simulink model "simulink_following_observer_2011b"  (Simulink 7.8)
settings: Solver=ode3  StartTime=0.0  StopTime=15  FixedStep=1e-2  RelTol=1e-3
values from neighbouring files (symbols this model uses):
  A = [0 1 0 0    [following_observer.m]
  Av = [0 1 0 0    [parameter_variation.m]
  B = [0; 1/M1; 0; 0]    [following_observer.m]
  Bv = [0; 1/M1v; 0; 0]    [parameter_variation.m]
  C = [0 0 1 0]    [following_observer.m]
  H = [-K 1]*inv(M0)*[zeros(4,1); 1]    [following_observer.m]
  K = -acker(A,B,p)    [following_observer.m]
  L = -acker(A',C',q)'    [following_observer.m]
  x0 = [-0.5 0 0.5 0]'    [parameter_variation.m]

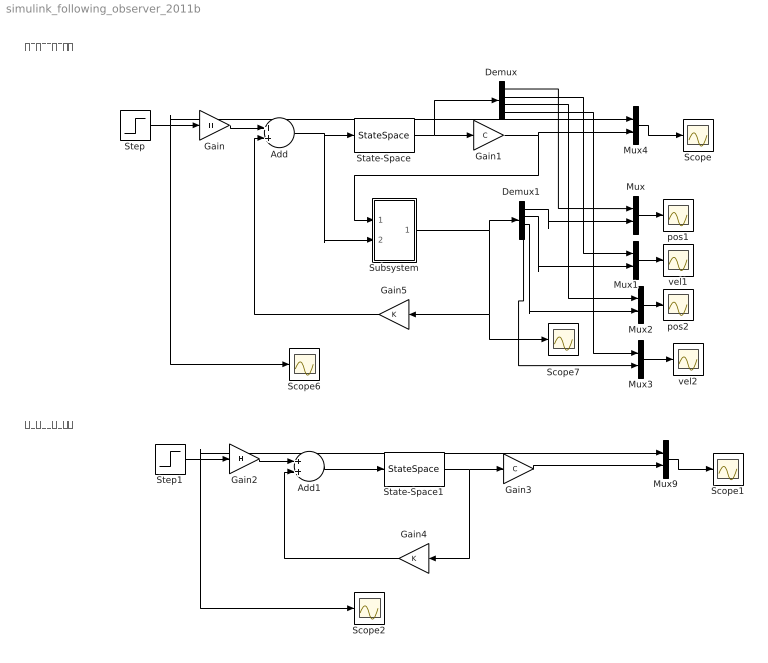
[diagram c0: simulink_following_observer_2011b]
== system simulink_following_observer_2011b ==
  note: 出力フィードバック
  note: 状態フィードバック
  Add : Sum
  Add1 : Sum
  Demux : Demux
  Demux1 : Demux
  Gain : Gain  Gain=H
  Gain1 : Gain  Gain=C  Multiplication=Matrix(K*u) (u vector)
  Gain2 : Gain  Gain=H
  Gain3 : Gain  Gain=C  Multiplication=Matrix(K*u) (u vector)
  Gain4 : Gain  Gain=K  Multiplication=Matrix(K*u) (u vector)
  Gain5 : Gain  Gain=K  Multiplication=Matrix(K*u) (u vector)
  Mux{,1..4,9} (6 alike) : Mux  Inputs=2
  Scope{,1..2,6..7} (5 alike) : Scope
  State-Space : StateSpace  A=Av  B=Bv  C=eye(4)  D=zeros(4,1)  X0=x0
  State-Space1 : StateSpace  A=Av  B=Bv  C=eye(4)  D=zeros(4,1)  X0=x0
  Step : Step  SampleTime=0
  Step1 : Step  SampleTime=0
  Subsystem : Subsystem
  pos1 : Scope
  pos2 : Scope
  vel1 : Scope
  vel2 : Scope
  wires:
  Gain/1 -> Add/1
  Add/1 -> State-Space/1, Subsystem/2(In2)
  State-Space/1 -> Gain1/1, Demux/1
  Gain1/1 -> Subsystem/1(In1), Mux4/2
  Step/1 -> Gain/1, Scope6/1, Mux4/1
  Gain5/1 -> Add/2
  Subsystem/1(Out1) -> Demux1/1, Gain5/1, Scope7/1
  Mux/1 -> pos1/1
  Mux1/1 -> vel1/1
  Mux2/1 -> pos2/1
  Mux3/1 -> vel2/1
  Demux/1 -> Mux/1
  Demux1/1 -> Mux/2
  Demux/2 -> Mux1/1
  Demux1/2 -> Mux1/2
  Demux/3 -> Mux2/1
  Demux1/3 -> Mux2/2
  Demux/4 -> Mux3/1
  Demux1/4 -> Mux3/2
  Mux4/1 -> Scope/1
  Gain2/1 -> Add1/1
  Add1/1 -> State-Space1/1
  State-Space1/1 -> Gain3/1, Gain4/1
  Gain3/1 -> Mux9/2
  Step1/1 -> Gain2/1, Scope2/1, Mux9/1
  Gain4/1 -> Add1/2
  Mux9/1 -> Scope1/1

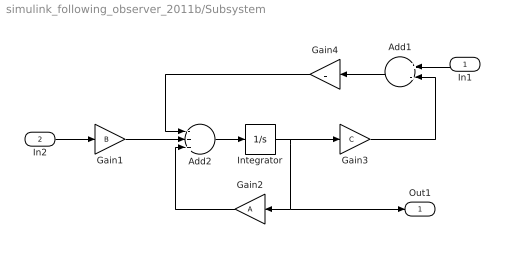
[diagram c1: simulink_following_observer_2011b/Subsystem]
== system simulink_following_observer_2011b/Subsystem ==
  In1 : Inport
  In2 : Inport  Port=2
  Add1 : Sum  Inputs=+-
  Add2 : Sum  Inputs=-++
  Gain1 : Gain  Gain=B  Multiplication=Matrix(K*u) (u vector)
  Gain2 : Gain  Gain=A  Multiplication=Matrix(K*u) (u vector)
  Gain3 : Gain  Gain=C  Multiplication=Matrix(K*u) (u vector)
  Gain4 : Gain  Gain=L  Multiplication=Matrix(K*u) (u vector)
  Integrator : Integrator
  Out1 : Outport
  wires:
  Gain4/1 -> Add2/1
  Add1/1 -> Gain4/1
  Gain3/1 -> Add1/2
  Gain2/1 -> Add2/3
  Add2/1 -> Integrator/1
  Integrator/1 -> Gain3/1, Gain2/1, Out1/1
  In1/1 -> Add1/1
  In2/1 -> Gain1/1
  Gain1/1 -> Add2/2
